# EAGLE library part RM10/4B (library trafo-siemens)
TRANSFORMER

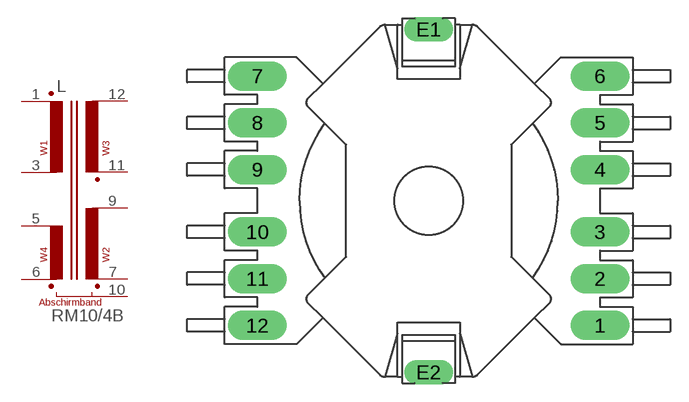
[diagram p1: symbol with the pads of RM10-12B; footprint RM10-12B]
Designator prefix L

## RM10/4B  [RM10-12B]
1  1A  pas
3  1E  pas
5  4E  pas
6  4A  pas
7  2A  pas
9  2E  pas
10  SCH  pas
11  3A  pas
12  3E  pas

## Footprint RM10-12B (pad centres in mm)
TRANSFORMER
drill 1.6 long: 1 13.97,-10.16; 2 13.97,-6.35; 3 13.97,-2.54; 4 13.97,2.54; 5 13.97,6.35; 6 13.97,10.16; 7 -13.97,10.16; 8 -13.97,6.35; 9 -13.97,2.54; 10 -13.97,-2.54; 11 -13.97,-6.35; 12 -13.97,-10.16
drill 1.321 long: E1 0,13.97; E2 0,-13.97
